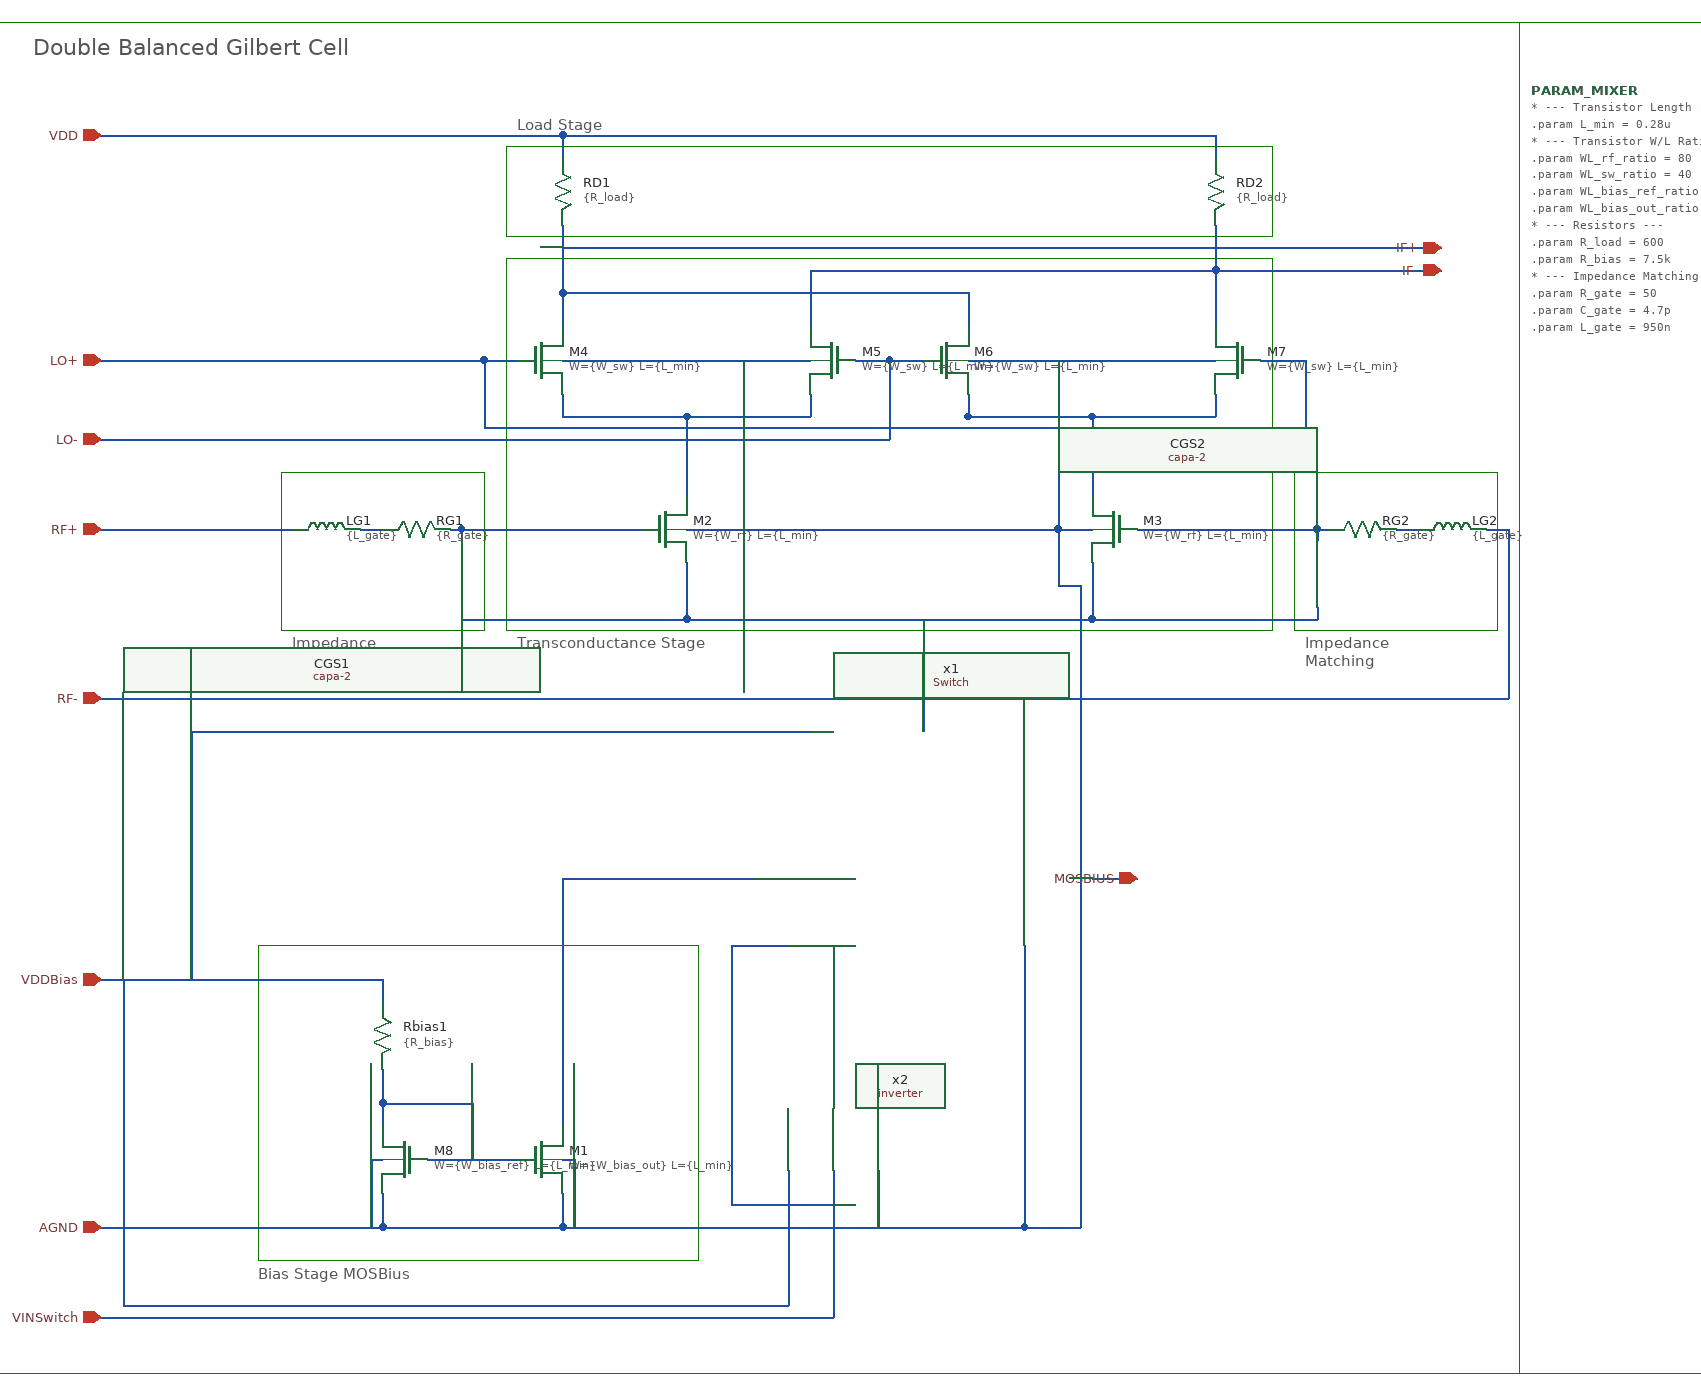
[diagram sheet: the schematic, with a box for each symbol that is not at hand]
v {xschem version=3.4.7 file_version=1.2}
G {}
K {}
V {}
S {}
E {}
P 4 5 320 -460 320 -180 710 -180 710 -460 320 -460 {}
P 4 1 680 -820 {}
P 4 5 1240 -880 1240 -740 1420 -740 1420 -880 1240 -880 {}
P 4 5 340 -880 340 -740 520 -740 520 -880 340 -880 {}
P 4 6 1440 -1250 1440 -80 1960 -80 1960 -1280 1440 -1280 1440 -1250 {}
P 4 5 540 -740 1220 -740 1220 -1070 540 -1070 540 -740 {}
P 4 5 540 -1090 1220 -1090 1220 -1170 540 -1170 540 -1090 {}
P 4 5 1440 -1280 70 -1280 70 -80 1440 -80 1440 -1280 {}
T {Bias Stage MOSBius} 320 -180 0 0 0.4 0.4 {}
T {Impedance
Matching} 1250 -740 0 0 0.4 0.4 {}
T {Transconductance Stage} 550 -740 0 0 0.4 0.4 {}
T {Impedance
Matching} 350 -740 0 0 0.4 0.4 {}
T {Load Stage} 550 -1200 0 0 0.4 0.4 {}
T {Double Balanced Gilbert Cell} 120 -1270 0 0 0.8 0.8 {}
N 430 -320 430 -300 {lab=#net1}
N 590 -320 590 -300 {lab=#net2}
N 430 -350 430 -320 {lab=#net1}
N 470 -270 550 -270 {lab=#net1}
N 430 -240 430 -210 {lab=AGND}
N 430 -210 590 -210 {lab=AGND}
N 590 -240 590 -210 {lab=AGND}
N 430 -430 430 -410 {lab=VDDBias}
N 280 -210 430 -210 {lab=AGND}
N 700 -800 700 -750 {lab=#net3}
N 1060 -800 1060 -750 {lab=#net3}
N 1330 -830 1350 -830 {lab=#net4}
N 1410 -830 1430 -830 {lab=RF-}
N 1260 -760 1260 -750 {lab=#net3}
N 1260 -830 1260 -820 {lab=#net5}
N 410 -830 430 -830 {lab=#net6}
N 490 -830 500 -830 {lab=#net7}
N 500 -830 500 -820 {lab=#net7}
N 500 -760 500 -750 {lab=#net3}
N 310 -830 350 -830 {lab=RF+}
N 700 -890 700 -860 {lab=#net8}
N 1060 -890 1060 -860 {lab=#net9}
N 1170 -950 1170 -930 {lab=#net9}
N 880 -980 910 -980 {lab=LO-}
N 1210 -980 1250 -980 {lab=LO+}
N 1060 -930 1060 -890 {lab=#net9}
N 1060 -930 1170 -930 {lab=#net9}
N 950 -930 1060 -930 {lab=#net9}
N 950 -950 950 -930 {lab=#net9}
N 810 -950 810 -930 {lab=#net8}
N 520 -980 550 -980 {lab=LO+}
N 700 -930 700 -890 {lab=#net8}
N 700 -930 810 -930 {lab=#net8}
N 590 -930 700 -930 {lab=#net8}
N 590 -950 590 -930 {lab=#net8}
N 1260 -830 1270 -830 {lab=#net5}
N 620 -830 660 -830 {lab=#net7}
N 1220 -830 1260 -830 {lab=#net5}
N 620 -750 700 -750 {lab=#net3}
N 910 -750 910 -710 {lab=#net3}
N 950 -930 1060 -930 {lab=#net9}
N 850 -980 880 -980 {lab=LO-}
N 700 -750 1060 -750 {lab=#net3}
N 590 -1040 590 -1010 {lab=IF+}
N 590 -1040 950 -1040 {lab=IF+}
N 950 -1040 950 -1010 {lab=IF+}
N 810 -1060 810 -1010 {lab=IF-}
N 810 -1060 1170 -1060 {lab=IF-}
N 1170 -1060 1170 -1010 {lab=IF-}
N 1170 -1100 1170 -1060 {lab=IF-}
N 590 -1100 590 -1040 {lab=IF+}
N 590 -1180 590 -1160 {lab=VDD}
N 590 -1180 1170 -1180 {lab=VDD}
N 1170 -1180 1170 -1160 {lab=VDD}
N 430 -1180 590 -1180 {lab=VDD}
N 1250 -980 1250 -920 {lab=LO+}
N 520 -920 1250 -920 {lab=LO+}
N 520 -980 520 -920 {lab=LO+}
N 430 -980 520 -980 {lab=LO+}
N 880 -980 880 -910 {lab=LO-}
N 430 -910 880 -910 {lab=LO-}
N 1170 -1060 1370 -1060 {lab=IF-}
N 590 -1080 1370 -1080 {lab=IF+}
N 590 -330 590 -320 {lab=#net2}
N 590 -210 740 -210 {lab=AGND}
N 1030 -830 1060 -830 {lab=AGND}
N 700 -830 1030 -830 {lab=AGND}
N 950 -980 1170 -980 {lab=AGND}
N 590 -980 810 -980 {lab=AGND}
N 1030 -980 1030 -830 {lab=AGND}
N 750 -980 750 -830 {lab=AGND}
N 430 -320 510 -320 {lab=#net1}
N 510 -320 510 -270 {lab=#net1}
N 590 -520 590 -450 {lab=#net2}
N 590 -450 590 -330 {lab=#net2}
N 180 -430 430 -430 {lab=VDDBias}
N 590 -270 600 -270 {lab=AGND}
N 600 -270 600 -210 {lab=AGND}
N 420 -270 430 -270 {lab=AGND}
N 420 -270 420 -210 {lab=AGND}
N 1100 -830 1220 -830 {lab=#net5}
N 1060 -750 1260 -750 {lab=#net3}
N 500 -750 620 -750 {lab=#net3}
N 500 -830 620 -830 {lab=#net7}
N 180 -830 310 -830 {lab=RF+}
N 180 -680 1430 -680 {lab=RF-}
N 1430 -830 1430 -680 {lab=RF-}
N 180 -1180 430 -1180 {lab=VDD}
N 180 -980 430 -980 {lab=LO+}
N 180 -910 430 -910 {lab=LO-}
N 1030 -830 1030 -780 {lab=AGND}
N 590 -520 730 -520 {lab=#net2}
N 260 -650 780 -650 {lab=VDDBias}
N 260 -650 260 -430 {lab=VDDBias}
N 740 -210 970 -210 {lab=AGND}
N 1000 -460 1000 -210 {lab=AGND}
N 870 -260 870 -210 {lab=AGND}
N 830 -250 830 -130 {lab=VINSwitch}
N 180 -130 800 -130 {lab=VINSwitch}
N 790 -260 790 -140 {lab=VDDBias}
N 200 -140 760 -140 {lab=VDDBias}
N 200 -430 200 -140 {lab=VDDBias}
N 970 -210 1000 -210 {lab=AGND}
N 760 -140 790 -140 {lab=VDDBias}
N 800 -130 830 -130 {lab=VINSwitch}
N 830 -260 830 -250 {lab=VINSwitch}
N 830 -460 830 -450 {lab=#net10}
N 740 -230 830 -230 {lab=VINSwitch}
N 740 -460 740 -230 {lab=VINSwitch}
N 740 -460 790 -460 {lab=VINSwitch}
N 730 -520 760 -520 {lab=#net2}
N 780 -650 810 -650 {lab=VDDBias}
N 910 -710 910 -650 {lab=#net3}
N 180 -210 280 -210 {lab=AGND}
N 1060 -520 1100 -520 {lab=MOSBIUS}
N 1030 -780 1040 -780 {lab=AGND}
N 1040 -780 1050 -780 {lab=AGND}
N 1050 -780 1050 -210 {lab=AGND}
N 1000 -210 1050 -210 {lab=AGND}
C {symbols/nfet_03v3.sym} 450 -270 0 1 {name=M8
L=\{L_min\}
W=\{W_bias_ref\}
nf=1
m=1
ad="'int((nf+1)/2) * W/nf * 0.18u'"
pd="'2*int((nf+1)/2) * (W/nf + 0.18u)'"
as="'int((nf+2)/2) * W/nf * 0.18u'"
ps="'2*int((nf+2)/2) * (W/nf + 0.18u)'"
nrd="'0.18u / W'" nrs="'0.18u / W'"
sa=0 sb=0 sd=0
model=nfet_03v3
spiceprefix=X
}
C {symbols/nfet_03v3.sym} 570 -270 0 0 {name=M1
L=\{L_min\}
W=\{W_bias_out\}
nf=1
m=1
ad="'int((nf+1)/2) * W/nf * 0.18u'"
pd="'2*int((nf+1)/2) * (W/nf + 0.18u)'"
as="'int((nf+2)/2) * W/nf * 0.18u'"
ps="'2*int((nf+2)/2) * (W/nf + 0.18u)'"
nrd="'0.18u / W'" nrs="'0.18u / W'"
sa=0 sb=0 sd=0
model=nfet_03v3
spiceprefix=X
}
C {symbols/nfet_03v3.sym} 1080 -830 0 1 {name=M3
L=\{L_min\}
W=\{W_rf\}
nf=1
m=1
ad="'int((nf+1)/2) * W/nf * 0.18u'"
pd="'2*int((nf+1)/2) * (W/nf + 0.18u)'"
as="'int((nf+2)/2) * W/nf * 0.18u'"
ps="'2*int((nf+2)/2) * (W/nf + 0.18u)'"
nrd="'0.18u / W'" nrs="'0.18u / W'"
sa=0 sb=0 sd=0
model=nfet_03v3
spiceprefix=X
}
C {symbols/nfet_03v3.sym} 680 -830 0 0 {name=M2
L=\{L_min\}
W=\{W_rf\}
nf=1
m=1
ad="'int((nf+1)/2) * W/nf * 0.18u'"
pd="'2*int((nf+1)/2) * (W/nf + 0.18u)'"
as="'int((nf+2)/2) * W/nf * 0.18u'"
ps="'2*int((nf+2)/2) * (W/nf + 0.18u)'"
nrd="'0.18u / W'" nrs="'0.18u / W'"
sa=0 sb=0 sd=0
model=nfet_03v3
spiceprefix=X
}
C {symbols/nfet_03v3.sym} 1190 -980 0 1 {name=M7
L=\{L_min\}
W=\{W_sw\}
nf=1
m=1
ad="'int((nf+1)/2) * W/nf * 0.18u'"
pd="'2*int((nf+1)/2) * (W/nf + 0.18u)'"
as="'int((nf+2)/2) * W/nf * 0.18u'"
ps="'2*int((nf+2)/2) * (W/nf + 0.18u)'"
nrd="'0.18u / W'" nrs="'0.18u / W'"
sa=0 sb=0 sd=0
model=nfet_03v3
spiceprefix=X
}
C {symbols/nfet_03v3.sym} 930 -980 0 0 {name=M6
L=\{L_min\}
W=\{W_sw\}
nf=1
m=1
ad="'int((nf+1)/2) * W/nf * 0.18u'"
pd="'2*int((nf+1)/2) * (W/nf + 0.18u)'"
as="'int((nf+2)/2) * W/nf * 0.18u'"
ps="'2*int((nf+2)/2) * (W/nf + 0.18u)'"
nrd="'0.18u / W'" nrs="'0.18u / W'"
sa=0 sb=0 sd=0
model=nfet_03v3
spiceprefix=X
}
C {symbols/nfet_03v3.sym} 830 -980 0 1 {name=M5
L=\{L_min\}
W=\{W_sw\}
nf=1
m=1
ad="'int((nf+1)/2) * W/nf * 0.18u'"
pd="'2*int((nf+1)/2) * (W/nf + 0.18u)'"
as="'int((nf+2)/2) * W/nf * 0.18u'"
ps="'2*int((nf+2)/2) * (W/nf + 0.18u)'"
nrd="'0.18u / W'" nrs="'0.18u / W'"
sa=0 sb=0 sd=0
model=nfet_03v3
spiceprefix=X
}
C {symbols/nfet_03v3.sym} 570 -980 0 0 {name=M4
L=\{L_min\}
W=\{W_sw\}
nf=1
m=1
ad="'int((nf+1)/2) * W/nf * 0.18u'"
pd="'2*int((nf+1)/2) * (W/nf + 0.18u)'"
as="'int((nf+2)/2) * W/nf * 0.18u'"
ps="'2*int((nf+2)/2) * (W/nf + 0.18u)'"
nrd="'0.18u / W'" nrs="'0.18u / W'"
sa=0 sb=0 sd=0
model=nfet_03v3
spiceprefix=X
}
C {devices/code_shown.sym} 1450 -1220 0 0 {name=PARAM_MIXER only_toplevel=false value="
* --- Transistor Length ---
.param L_min = 0.28u

* --- Transistor W/L Ratios ---
.param WL_rf_ratio       = 80
.param WL_sw_ratio       = 40
.param WL_bias_ref_ratio = 10
.param WL_bias_out_ratio = 60

* --- Resistors ---
.param R_load = 600
.param R_bias = 7.5k

* --- Impedance Matching ---
.param R_gate = 50
.param C_gate = 4.7p
.param L_gate = 950n

* --- Calculated Transistor Widths ---
.param W_rf       = \{WL_rf_ratio * L_min\}
.param W_sw       = \{WL_sw_ratio * L_min\}
.param W_bias_ref = \{WL_bias_ref_ratio * L_min\}
.param W_bias_out = \{WL_bias_out_ratio * L_min\}
"}
C {devices/res.sym} 590 -1130 0 0 {name=RD1
value=\{R_load\}
footprint=1206
device=resistor
m=1}
C {devices/res.sym} 1170 -1130 0 0 {name=RD2
value=\{R_load\}
footprint=1206
device=resistor
m=1}
C {devices/capa-2.sym} 500 -790 0 0 {name=CGS1
m=1
value=\{C_gate\}
footprint=1206
device=polarized_capacitor}
C {devices/capa-2.sym} 1260 -790 0 0 {name=CGS2
m=1
value=\{C_gate\}
footprint=1206
device=polarized_capacitor}
C {devices/res.sym} 460 -830 3 0 {name=RG1
value=\{R_gate\}
footprint=1206
device=resistor
m=1}
C {devices/res.sym} 1300 -830 3 0 {name=RG2
value=\{R_gate\}
footprint=1206
device=resistor
m=1}
C {devices/ind.sym} 380 -830 3 0 {name=LG1
m=1
value=\{L_gate\}
footprint=1206
device=inductor}
C {devices/ind.sym} 1380 -830 3 0 {name=LG2
m=1
value=\{L_gate\}
footprint=1206
device=inductor}
C {devices/res.sym} 430 -380 0 0 {name=Rbias1
value=\{R_bias\}
footprint=1206
device=resistor
m=1}
C {devices/ipin.sym} 180 -210 0 0 {name=p1 lab=AGND}
C {devices/iopin.sym} 180 -680 2 0 {name=p3 lab=RF-}
C {devices/iopin.sym} 1370 -1080 0 0 {name=p4 lab=IF+}
C {devices/ipin.sym} 180 -1180 0 0 {name=p5 lab=VDD}
C {devices/ipin.sym} 180 -980 0 0 {name=p6 lab=LO+}
C {devices/ipin.sym} 180 -910 0 0 {name=p7 lab=LO-}
C {devices/iopin.sym} 1370 -1060 0 0 {name=p8 lab=IF-}
C {devices/iopin.sym} 180 -830 2 0 {name=p9 lab=RF+}
C {devices/ipin.sym} 180 -430 0 0 {name=p2 lab=VDDBias}
C {devices/iopin.sym} 1100 -520 0 0 {name=p10 lab=MOSBIUS}
C {gf180mcuD/test/inverter.sym} 830 -410 3 0 {name=x2}
C {devices/ipin.sym} 180 -130 0 0 {name=p11 lab=VINSwitch}
C {gf180mcuD/mixer/Switch.sym} 910 -560 0 0 {name=x1}
